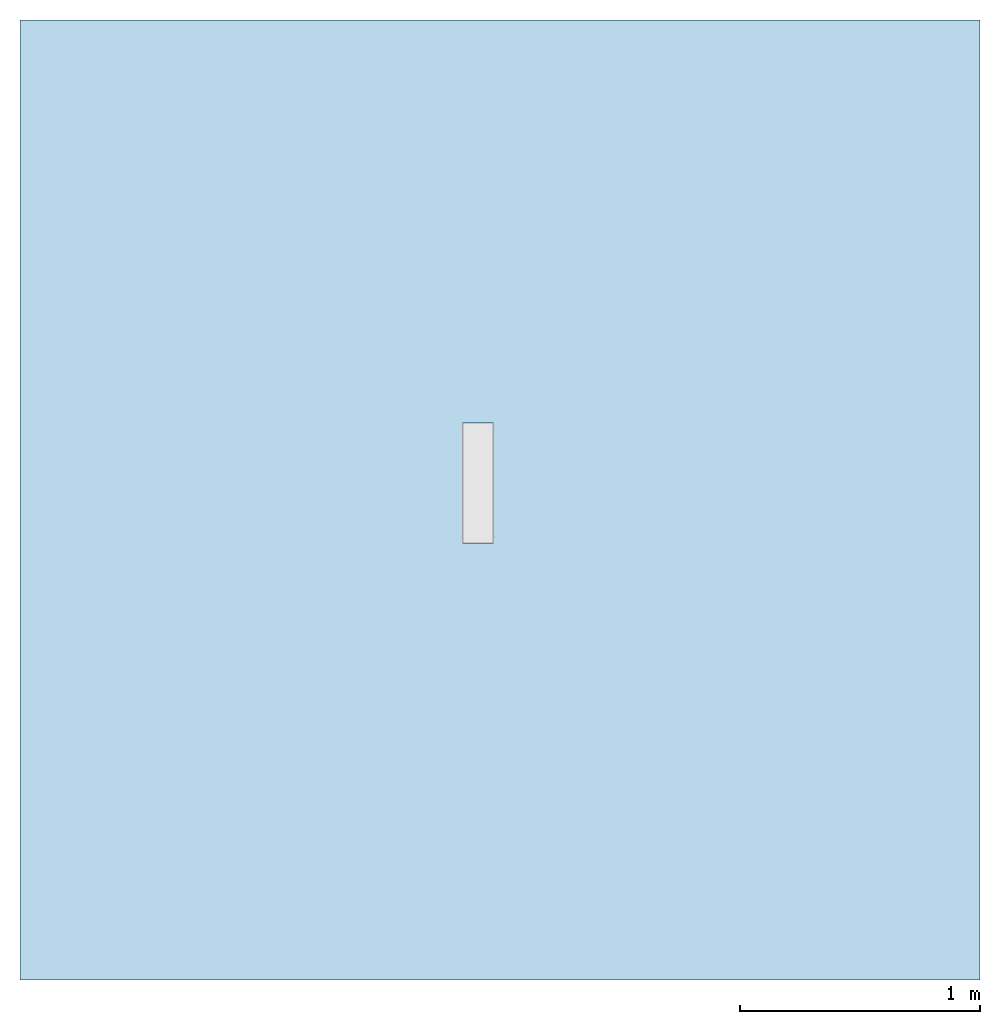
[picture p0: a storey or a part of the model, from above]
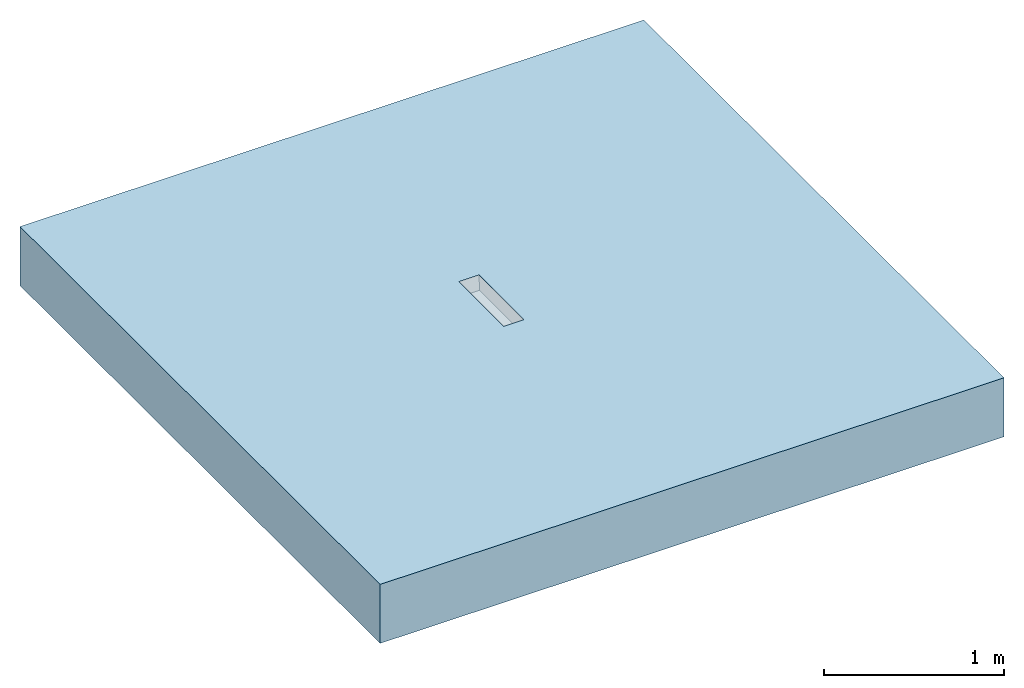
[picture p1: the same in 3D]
Properties of the parts of a building model (IFC2X3)

# File
Description: ViewDefinition [CoordinationView]
File name: Project Number
Time: 2014-06-06T14:14:24
Written by: The EXPRESS Data Manager Version 5.01.0100.02.64mod : 6 Jun 2012
Made in: 20130308_1515(x64) - Exporter 2014.0.2013.0308 - Default UI
Comment: STEP Physical File produced by: The EXPRESS Data Manager Version 5.01.0100.02.64mod : 6 Jun 2012 * Module: EDMstepFileFactory/EDMstandAlone * Creation date: Fri Jun 06 14:14:24 2014 * Host: IN-BLR-PC-0010 * Database: C:\Users\palleri\AppData\Local\Temp\{CDFD5F90-8A38-4B86-A5C0-3FB1EAF5F847}\ifc * Database version: 5507 * Database creation date: Fri Jun 06 14:14:22 2014 * Schema: IFC2X3 * Model: DataRepository.ifc * Model creation date: Fri Jun 06 14:14:22 2014 * Header model: DataRepository.ifc_HeaderModel * Header model creation date: Fri Jun 06 14:14:22 2014 * EDMuser: sdai-user * EDMgroup: sdai-group * License ID and type: 5605 : Permanent license. Expiry date: * EDMstepFileFactory options: 020000

# IfcProject, Project Number
LongName: Project Name; Phase: Project Status

# IfcSite, Default
RefLatitude: 42, 21, 30, 344238; RefLongitude: -71, -3, -35, -194702; RefElevation: 0 mm

# IfcBuilding
Pset_BuildingCommon - NumberOfStoreys: 1
Other - Project Status: Project Status; Project Address: ## Street City, State Zip; Project Number: Project Number; Project Issue Date: Issue Date; Client Name: Owner; Project Name: Project Name

# IfcBuildingStorey, Level 1
LongName: Level 1; Elevation: 0 mm
Constraints - Elevation Base: Project Base Point; Elevation: 0 mm
Graphics - Symbol at End 2 Default: yes; Line Pattern: Center; Symbol: M_Level Head - Circle: M_Level Head - Circle; Color: 0; Line Weight: 1; Symbol at End 1 Default: no
Identity Data - Name: Level 1; Structural: no; Building Story: yes
Dimensions - Computation Height: 0 mm

# IfcFlowTerminal: 36789 - Adjustable Channel - Intermediate Section - 500mm LG - Invert Depth 75/105mm, ACO Freedeck Adjustable Height Channel Intermediate Section Galvanized Steel:36789 - Adjustable Channel - Intermediate Section - 500mm LG - Invert Depth 75/105mm:309511
In: Level 1
Material: Galvanized Steel
Dimensions - Height @ Invert 2 (75 - 105mm): 105 mm; Height @ Invert 1 (75 - 105mm): 105 mm; Grating End Length: 500 mm; Channel End Length: -500 mm
Construction - 36952 - Grating - Plain Mesh - Galvanised Steel - 500mm long: yes; End Plate Invert 1: no; End Plate Invert 2: no; 00277 - Grating - Slotted Grating - Galvanised Steel - 500mm long: no; 36953 - Grating - Plain Mesh - Galvanised Steel - 1000mm long: no; 00276 - Grating - Slotted Grating - Galvanised Steel - 1000mm long: no
Other - Top Piece Void Height @ Invert 1: 45 mm; Height @ Invert 2 Min & Max: 105 mm; Height @ Invert 1 Min & Max: 105 mm; Top Piece Void Height @ Invert 2: 45 mm; Nos: 16
Constraints - Level: Level: Level 1; Moves With Nearby Elements: no
Phasing - Phase Created: New Construction
Identity Data - Mark: 28; Manufacturer: ACO Building Drainage; E-mail Sales: abdcommercial@aco.co.uk; Website: www.acobd.com; Address: ACO Business Centre, Caxton Road, Bedford, MK41 0LF; Watermark2: This file is water marked and users are prohibited to reproduce, adapt, distribute this information; Fax: +44 (0)1462 851490; E-mail Technical: abdtechnical@aco.co.uk; Watermarked By: www.acobd.com; Watermarked With: BIM Manager Premium Suite; Watermark1: This file is the property of ACO Technologies PLC; Telephone: +44 (0)1462 816666
Pset_ManufacturerTypeInformation - Manufacturer: ACO Building Drainage
Model Properties - Grating Product Code 00277: Load Class A15 - Slotted Grating - 10 x 80mm Slot - Galvanized Steel - 500mm long - 1.0kg; End Plate Product Code 36793: End Plate Galvanized Steel for Invert Depth - 75/105mm - 0.1Kg; Grating Product Code 36953: Load Class A15 - Mesh Grating - 14mm x 30mm Mesh - Galvanized Steel - 1000mm long - 3.0kg; Grating Product Code 00276: Load Class A15 - Slotted Grating - 10 x 80mm Slot - Galvanized Steel - 1000mm long - 2.2kg; Grating Product Code 36952: Load Class A15 - Mesh Grating - 14mm x 30mm Mesh - Galvanized Steel - 500mm long - 1.6kg
General - Maintenance Guidelines: X:\Electronic Literature\ABD Electronic Literature\Roof and Balcony Drainage\ACO Freedeck Brochure.pdf; NBS Specification: NBS Section R10 Gravity Rainwater Drainage Systems, Subsection 365; Product Description: ACO Freedeck Adjustable Channel - Intermediate Section; Dimensions (LxWxH): 500 x 130 x 75/105; Product Type: Linear Deck Drainage System; Product Code: 36789; Channel Material: Hot Dipped Galvanised Steel; Weight (Kg): 3.3kg; Product Range: ACO Freedeck; Price: POA - contact ACO; Channel Recyclable: Fully recyclable; Channel Recycled Material Content: 25 - 30 %; Load Class: A15; Channel Colour: Galvanised; Installation Guidelines: X:\Electronic Literature\ABD Electronic Literature\Roof and Balcony Drainage\ACO Freedeck Brochure.pdf; Product Standard: BS EN 1433:2002, CE marked
Materials and Finishes - Material: Galvanized Steel

# IfcOpeningElement: Recess
In: Level 1
Phasing - Phase Created: New Construction
Dimensions - Thickness: 400 mm; Volume: 6.39306 m3; Area: 16 m2; Perimeter: 16000 mm
Structural - Structural: no; Enable Analytical Model: no
Constraints - Level: Level: Level 1; Related to Mass: no; Height Offset From Level: 0 mm; Room Bounding: yes
Graphics - Coarse Scale Fill Color: 0
Analytical Properties - Absorptance: 0.1; Thermal Resistance (R): 0.382409; Roughness: 1; Thermal mass: 604440; Heat Transfer Coefficient (U): 2.615
Construction - Function: Interior; Default Thickness: 400 mm
Materials and Finishes - Structural Material: Concrete, Broom Finish

# IfcSlab: Floor:Generic Floor - 400mm, Floor:Generic Floor - 400mm:193825
In: Level 1
PredefinedType: FLOOR; Material: Concrete, Broom Finish 400 mm
Phasing - Phase Created: New Construction
Dimensions - Thickness: 400 mm; Volume: 6.39306 m3; Area: 16 m2; Perimeter: 16000 mm
Structural - Structural: no; Enable Analytical Model: no
Constraints - Level: Level: Level 1; Related to Mass: no; Height Offset From Level: 0 mm; Room Bounding: yes
Pset_SlabCommon - Reference: Generic Floor - 400mm; IsExternal: no; LoadBearing: yes; ThermalTransmittance: 2.615 kg/K/s3
Graphics - Coarse Scale Fill Color: 0
Analytical Properties - Absorptance: 0.1; Thermal Resistance (R): 0.382409; Roughness: 1; Thermal mass: 604440; Heat Transfer Coefficient (U): 2.615
Construction - Function: Interior; Default Thickness: 400 mm
Materials and Finishes - Structural Material: Concrete, Broom Finish
